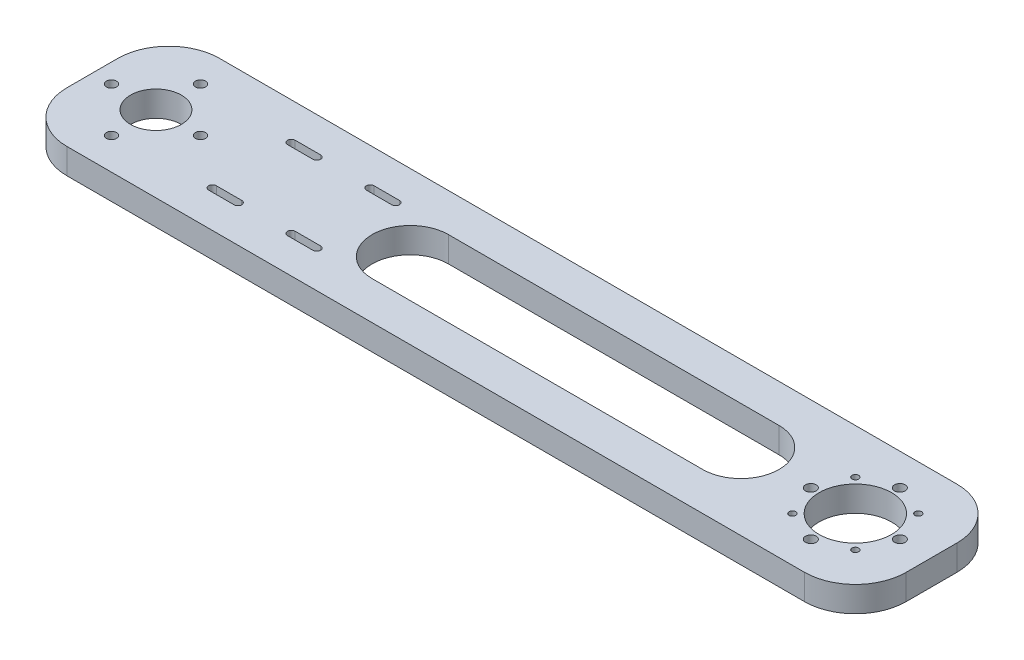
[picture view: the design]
ISO-10303-21;
HEADER;
FILE_DESCRIPTION(('STEP AP214'),'2;1');
FILE_NAME('part.step','',(''),(''),'','','');
FILE_SCHEMA(('AUTOMOTIVE_DESIGN { 1 0 10303 214 1 1 1 1 }'));
ENDSEC;
DATA;
#1=APPLICATION_CONTEXT('core data for automotive mechanical design processes');
#2=APPLICATION_PROTOCOL_DEFINITION('international standard','automotive_design',2000,#1);
#3=PRODUCT_CONTEXT('',#1,'mechanical');
#4=PRODUCT('Part','Part','',(#3));
#5=PRODUCT_RELATED_PRODUCT_CATEGORY('part','',(#4));
#6=PRODUCT_DEFINITION_FORMATION('','',#4);
#7=PRODUCT_DEFINITION_CONTEXT('part definition',#1,'design');
#8=PRODUCT_DEFINITION('design','',#6,#7);
#9=PRODUCT_DEFINITION_SHAPE('','',#8);
#10=(LENGTH_UNIT() NAMED_UNIT(*) SI_UNIT(.MILLI.,.METRE.));
#11=(NAMED_UNIT(*) PLANE_ANGLE_UNIT() SI_UNIT($,.RADIAN.));
#12=(NAMED_UNIT(*) SI_UNIT($,.STERADIAN.) SOLID_ANGLE_UNIT());
#13=UNCERTAINTY_MEASURE_WITH_UNIT(LENGTH_MEASURE(1.E-05),#10,'distance_accuracy_value','');
#14=(GEOMETRIC_REPRESENTATION_CONTEXT(3) GLOBAL_UNCERTAINTY_ASSIGNED_CONTEXT((#13)) GLOBAL_UNIT_ASSIGNED_CONTEXT((#10,
#11,#12)) REPRESENTATION_CONTEXT('',''));
#15=CARTESIAN_POINT('',(0.,0.,0.));
#16=DIRECTION('',(0.,0.,1.));
#17=DIRECTION('',(1.,0.,0.));
#18=AXIS2_PLACEMENT_3D('',#15,#16,#17);
#19=CARTESIAN_POINT('',(165.,10.,30.));
#20=DIRECTION('',(-1.,0.,0.));
#21=DIRECTION('',(0.,0.,1.));
#22=AXIS2_PLACEMENT_3D('',#19,#20,#21);
#23=PLANE('',#22);
#24=DIRECTION('',(0.,0.,-1.));
#25=VECTOR('',#24,1.);
#26=CARTESIAN_POINT('',(165.,0.,30.));
#27=LINE('',#26,#25);
#28=CARTESIAN_POINT('',(165.,0.,10.));
#29=VERTEX_POINT('',#28);
#30=CARTESIAN_POINT('',(165.,0.,-9.99999999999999));
#31=VERTEX_POINT('',#30);
#32=EDGE_CURVE('E468',#29,#31,#27,.T.);
#33=ORIENTED_EDGE('',*,*,#32,.T.);
#34=DIRECTION('',(0.,-1.,0.));
#35=VECTOR('',#34,1.);
#36=CARTESIAN_POINT('',(165.,10.,-9.99999999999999));
#37=LINE('',#36,#35);
#38=CARTESIAN_POINT('',(165.,10.,-9.99999999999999));
#39=VERTEX_POINT('',#38);
#40=EDGE_CURVE('E12',#31,#39,#37,.F.);
#41=ORIENTED_EDGE('',*,*,#40,.T.);
#42=DIRECTION('',(0.,0.,-1.));
#43=VECTOR('',#42,1.);
#44=CARTESIAN_POINT('',(165.,10.,30.));
#45=LINE('',#44,#43);
#46=CARTESIAN_POINT('',(165.,10.,10.));
#47=VERTEX_POINT('',#46);
#48=EDGE_CURVE('E471',#47,#39,#45,.T.);
#49=ORIENTED_EDGE('',*,*,#48,.F.);
#50=DIRECTION('',(0.,-1.,0.));
#51=VECTOR('',#50,1.);
#52=CARTESIAN_POINT('',(165.,10.,10.));
#53=LINE('',#52,#51);
#54=EDGE_CURVE('E58',#47,#29,#53,.T.);
#55=ORIENTED_EDGE('',*,*,#54,.T.);
#56=EDGE_LOOP('',(#33,#41,#49,#55));
#57=FACE_BOUND('',#56,.T.);
#58=ADVANCED_FACE('F55',(#57),#23,.F.);
#59=CARTESIAN_POINT('',(-165.,10.,-30.));
#60=DIRECTION('',(0.,0.,1.));
#61=DIRECTION('',(1.,0.,0.));
#62=AXIS2_PLACEMENT_3D('',#59,#60,#61);
#63=PLANE('',#62);
#64=DIRECTION('',(-1.,0.,0.));
#65=VECTOR('',#64,1.);
#66=CARTESIAN_POINT('',(-165.,0.,-30.));
#67=LINE('',#66,#65);
#68=CARTESIAN_POINT('',(145.,0.,-30.));
#69=VERTEX_POINT('',#68);
#70=CARTESIAN_POINT('',(-145.,0.,-30.));
#71=VERTEX_POINT('',#70);
#72=EDGE_CURVE('E490',#69,#71,#67,.T.);
#73=ORIENTED_EDGE('',*,*,#72,.T.);
#74=DIRECTION('',(0.,-1.,0.));
#75=VECTOR('',#74,1.);
#76=CARTESIAN_POINT('',(-145.,10.,-30.));
#77=LINE('',#76,#75);
#78=CARTESIAN_POINT('',(-145.,10.,-30.));
#79=VERTEX_POINT('',#78);
#80=EDGE_CURVE('E508',#71,#79,#77,.F.);
#81=ORIENTED_EDGE('',*,*,#80,.T.);
#82=DIRECTION('',(-1.,0.,0.));
#83=VECTOR('',#82,1.);
#84=CARTESIAN_POINT('',(-165.,10.,-30.));
#85=LINE('',#84,#83);
#86=CARTESIAN_POINT('',(145.,10.,-30.));
#87=VERTEX_POINT('',#86);
#88=EDGE_CURVE('E473',#87,#79,#85,.T.);
#89=ORIENTED_EDGE('',*,*,#88,.F.);
#90=DIRECTION('',(0.,-1.,0.));
#91=VECTOR('',#90,1.);
#92=CARTESIAN_POINT('',(145.,10.,-30.));
#93=LINE('',#92,#91);
#94=EDGE_CURVE('E510',#87,#69,#93,.T.);
#95=ORIENTED_EDGE('',*,*,#94,.T.);
#96=EDGE_LOOP('',(#73,#81,#89,#95));
#97=FACE_BOUND('',#96,.T.);
#98=ADVANCED_FACE('F545',(#97),#63,.F.);
#99=CARTESIAN_POINT('',(-165.,10.,30.));
#100=DIRECTION('',(1.,0.,0.));
#101=DIRECTION('',(0.,0.,-1.));
#102=AXIS2_PLACEMENT_3D('',#99,#100,#101);
#103=PLANE('',#102);
#104=DIRECTION('',(0.,0.,1.));
#105=VECTOR('',#104,1.);
#106=CARTESIAN_POINT('',(-165.,10.,30.));
#107=LINE('',#106,#105);
#108=CARTESIAN_POINT('',(-165.,10.,-9.99999999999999));
#109=VERTEX_POINT('',#108);
#110=CARTESIAN_POINT('',(-165.,10.,10.));
#111=VERTEX_POINT('',#110);
#112=EDGE_CURVE('E480',#109,#111,#107,.T.);
#113=ORIENTED_EDGE('',*,*,#112,.F.);
#114=DIRECTION('',(0.,-1.,0.));
#115=VECTOR('',#114,1.);
#116=CARTESIAN_POINT('',(-165.,10.,-9.99999999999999));
#117=LINE('',#116,#115);
#118=CARTESIAN_POINT('',(-165.,0.,-9.99999999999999));
#119=VERTEX_POINT('',#118);
#120=EDGE_CURVE('E496',#109,#119,#117,.T.);
#121=ORIENTED_EDGE('',*,*,#120,.T.);
#122=DIRECTION('',(0.,0.,1.));
#123=VECTOR('',#122,1.);
#124=CARTESIAN_POINT('',(-165.,0.,30.));
#125=LINE('',#124,#123);
#126=CARTESIAN_POINT('',(-165.,0.,10.));
#127=VERTEX_POINT('',#126);
#128=EDGE_CURVE('E487',#119,#127,#125,.T.);
#129=ORIENTED_EDGE('',*,*,#128,.T.);
#130=DIRECTION('',(0.,-1.,0.));
#131=VECTOR('',#130,1.);
#132=CARTESIAN_POINT('',(-165.,10.,10.));
#133=LINE('',#132,#131);
#134=EDGE_CURVE('E485',#127,#111,#133,.F.);
#135=ORIENTED_EDGE('',*,*,#134,.T.);
#136=EDGE_LOOP('',(#113,#121,#129,#135));
#137=FACE_BOUND('',#136,.T.);
#138=ADVANCED_FACE('F551',(#137),#103,.F.);
#139=CARTESIAN_POINT('',(-165.,10.,30.));
#140=DIRECTION('',(0.,0.,-1.));
#141=DIRECTION('',(-1.,0.,0.));
#142=AXIS2_PLACEMENT_3D('',#139,#140,#141);
#143=PLANE('',#142);
#144=DIRECTION('',(1.,0.,0.));
#145=VECTOR('',#144,1.);
#146=CARTESIAN_POINT('',(-165.,10.,30.));
#147=LINE('',#146,#145);
#148=CARTESIAN_POINT('',(-145.,10.,30.));
#149=VERTEX_POINT('',#148);
#150=CARTESIAN_POINT('',(145.,10.,30.));
#151=VERTEX_POINT('',#150);
#152=EDGE_CURVE('E483',#149,#151,#147,.T.);
#153=ORIENTED_EDGE('',*,*,#152,.F.);
#154=DIRECTION('',(0.,-1.,0.));
#155=VECTOR('',#154,1.);
#156=CARTESIAN_POINT('',(-145.,10.,30.));
#157=LINE('',#156,#155);
#158=CARTESIAN_POINT('',(-145.,0.,30.));
#159=VERTEX_POINT('',#158);
#160=EDGE_CURVE('E522',#149,#159,#157,.T.);
#161=ORIENTED_EDGE('',*,*,#160,.T.);
#162=DIRECTION('',(1.,0.,0.));
#163=VECTOR('',#162,1.);
#164=CARTESIAN_POINT('',(-165.,0.,30.));
#165=LINE('',#164,#163);
#166=CARTESIAN_POINT('',(145.,0.,30.));
#167=VERTEX_POINT('',#166);
#168=EDGE_CURVE('E475',#159,#167,#165,.T.);
#169=ORIENTED_EDGE('',*,*,#168,.T.);
#170=DIRECTION('',(0.,-1.,0.));
#171=VECTOR('',#170,1.);
#172=CARTESIAN_POINT('',(145.,10.,30.));
#173=LINE('',#172,#171);
#174=EDGE_CURVE('E519',#167,#151,#173,.F.);
#175=ORIENTED_EDGE('',*,*,#174,.T.);
#176=EDGE_LOOP('',(#153,#161,#169,#175));
#177=FACE_BOUND('',#176,.T.);
#178=ADVANCED_FACE('F559',(#177),#143,.F.);
#179=CARTESIAN_POINT('',(0.,10.,0.));
#180=DIRECTION('',(0.,-1.,0.));
#181=DIRECTION('',(0.,0.,-1.));
#182=AXIS2_PLACEMENT_3D('',#179,#180,#181);
#183=PLANE('',#182);
#184=CARTESIAN_POINT('',(-122.499999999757,10.,1.13742348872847E-10));
#185=DIRECTION('',(0.,1.,0.));
#186=DIRECTION('',(-1.,0.,0.));
#187=AXIS2_PLACEMENT_3D('',#184,#185,#186);
#188=CIRCLE('',#187,2.);
#189=CARTESIAN_POINT('',(-124.499999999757,10.,1.1373536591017E-10));
#190=VERTEX_POINT('',#189);
#191=EDGE_CURVE('E1002',#190,#190,#188,.T.);
#192=ORIENTED_EDGE('',*,*,#191,.F.);
#193=EDGE_LOOP('',(#192));
#194=FACE_BOUND('',#193,.T.);
#195=CARTESIAN_POINT('',(-140.,10.,17.5000000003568));
#196=DIRECTION('',(0.,1.,0.));
#197=DIRECTION('',(0.,0.,-1.));
#198=AXIS2_PLACEMENT_3D('',#195,#196,#197);
#199=CIRCLE('',#198,2.);
#200=CARTESIAN_POINT('',(-140.,10.,15.5000000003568));
#201=VERTEX_POINT('',#200);
#202=EDGE_CURVE('E998',#201,#201,#199,.T.);
#203=ORIENTED_EDGE('',*,*,#202,.F.);
#204=EDGE_LOOP('',(#203));
#205=FACE_BOUND('',#204,.T.);
#206=CARTESIAN_POINT('',(-157.500000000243,10.,1.13492548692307E-10));
#207=DIRECTION('',(0.,1.,0.));
#208=DIRECTION('',(1.,0.,0.));
#209=AXIS2_PLACEMENT_3D('',#206,#207,#208);
#210=CIRCLE('',#209,2.);
#211=CARTESIAN_POINT('',(-155.500000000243,10.,1.1351349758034E-10));
#212=VERTEX_POINT('',#211);
#213=EDGE_CURVE('E259',#212,#212,#210,.T.);
#214=ORIENTED_EDGE('',*,*,#213,.F.);
#215=EDGE_LOOP('',(#214));
#216=FACE_BOUND('',#215,.T.);
#217=DIRECTION('',(1.,0.,0.));
#218=VECTOR('',#217,1.);
#219=CARTESIAN_POINT('',(-40.,10.,15.));
#220=LINE('',#219,#218);
#221=CARTESIAN_POINT('',(-40.,10.,15.));
#222=VERTEX_POINT('',#221);
#223=CARTESIAN_POINT('',(90.,10.,15.));
#224=VERTEX_POINT('',#223);
#225=EDGE_CURVE('E266',#222,#224,#220,.T.);
#226=ORIENTED_EDGE('',*,*,#225,.F.);
#227=CARTESIAN_POINT('',(-40.,10.,0.));
#228=DIRECTION('',(0.,1.,0.));
#229=DIRECTION('',(0.,0.,1.));
#230=AXIS2_PLACEMENT_3D('',#227,#228,#229);
#231=CIRCLE('',#230,15.);
#232=CARTESIAN_POINT('',(-40.,10.,-15.));
#233=VERTEX_POINT('',#232);
#234=EDGE_CURVE('E70',#233,#222,#231,.T.);
#235=ORIENTED_EDGE('',*,*,#234,.F.);
#236=DIRECTION('',(-1.,0.,0.));
#237=VECTOR('',#236,1.);
#238=CARTESIAN_POINT('',(-40.,10.,-15.));
#239=LINE('',#238,#237);
#240=CARTESIAN_POINT('',(90.,10.,-15.));
#241=VERTEX_POINT('',#240);
#242=EDGE_CURVE('E253',#241,#233,#239,.T.);
#243=ORIENTED_EDGE('',*,*,#242,.F.);
#244=CARTESIAN_POINT('',(90.,10.,0.));
#245=DIRECTION('',(0.,1.,0.));
#246=DIRECTION('',(0.,0.,1.));
#247=AXIS2_PLACEMENT_3D('',#244,#245,#246);
#248=CIRCLE('',#247,15.);
#249=EDGE_CURVE('E257',#224,#241,#248,.T.);
#250=ORIENTED_EDGE('',*,*,#249,.F.);
#251=EDGE_LOOP('',(#226,#235,#243,#250));
#252=FACE_BOUND('',#251,.T.);
#253=CARTESIAN_POINT('',(135.,10.,17.5));
#254=DIRECTION('',(0.,-1.,0.));
#255=DIRECTION('',(0.,0.,-1.));
#256=AXIS2_PLACEMENT_3D('',#253,#254,#255);
#257=CIRCLE('',#256,2.09999999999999);
#258=CARTESIAN_POINT('',(135.,10.,15.4));
#259=VERTEX_POINT('',#258);
#260=EDGE_CURVE('E280',#259,#259,#257,.T.);
#261=ORIENTED_EDGE('',*,*,#260,.T.);
#262=EDGE_LOOP('',(#261));
#263=FACE_BOUND('',#262,.T.);
#264=CARTESIAN_POINT('',(152.5,10.,0.));
#265=DIRECTION('',(0.,-1.,0.));
#266=DIRECTION('',(0.,0.,-1.));
#267=AXIS2_PLACEMENT_3D('',#264,#265,#266);
#268=CIRCLE('',#267,2.09999999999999);
#269=CARTESIAN_POINT('',(152.5,10.,-2.09999999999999));
#270=VERTEX_POINT('',#269);
#271=EDGE_CURVE('E286',#270,#270,#268,.T.);
#272=ORIENTED_EDGE('',*,*,#271,.T.);
#273=EDGE_LOOP('',(#272));
#274=FACE_BOUND('',#273,.T.);
#275=CARTESIAN_POINT('',(117.5,10.,0.));
#276=DIRECTION('',(0.,-1.,0.));
#277=DIRECTION('',(0.,0.,-1.));
#278=AXIS2_PLACEMENT_3D('',#275,#276,#277);
#279=CIRCLE('',#278,2.1);
#280=CARTESIAN_POINT('',(117.5,10.,-2.1));
#281=VERTEX_POINT('',#280);
#282=EDGE_CURVE('E293',#281,#281,#279,.T.);
#283=ORIENTED_EDGE('',*,*,#282,.T.);
#284=EDGE_LOOP('',(#283));
#285=FACE_BOUND('',#284,.T.);
#286=CARTESIAN_POINT('',(135.,10.,-17.5));
#287=DIRECTION('',(0.,-1.,0.));
#288=DIRECTION('',(0.,0.,-1.));
#289=AXIS2_PLACEMENT_3D('',#286,#287,#288);
#290=CIRCLE('',#289,2.09999999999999);
#291=CARTESIAN_POINT('',(135.,10.,-19.6));
#292=VERTEX_POINT('',#291);
#293=EDGE_CURVE('E273',#292,#292,#290,.T.);
#294=ORIENTED_EDGE('',*,*,#293,.T.);
#295=EDGE_LOOP('',(#294));
#296=FACE_BOUND('',#295,.T.);
#297=CARTESIAN_POINT('',(-140.,10.,-17.5000000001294));
#298=DIRECTION('',(0.,1.,0.));
#299=DIRECTION('',(0.,0.,1.));
#300=AXIS2_PLACEMENT_3D('',#297,#298,#299);
#301=CIRCLE('',#300,2.);
#302=CARTESIAN_POINT('',(-140.,10.,-15.5000000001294));
#303=VERTEX_POINT('',#302);
#304=EDGE_CURVE('E279',#303,#303,#301,.T.);
#305=ORIENTED_EDGE('',*,*,#304,.F.);
#306=EDGE_LOOP('',(#305));
#307=FACE_BOUND('',#306,.T.);
#308=DIRECTION('',(-1.,0.,0.));
#309=VECTOR('',#308,1.);
#310=CARTESIAN_POINT('',(-102.265379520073,10.,-14.));
#311=LINE('',#310,#309);
#312=CARTESIAN_POINT('',(-92.2653795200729,10.,-14.));
#313=VERTEX_POINT('',#312);
#314=CARTESIAN_POINT('',(-102.265379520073,10.,-14.));
#315=VERTEX_POINT('',#314);
#316=EDGE_CURVE('E345',#313,#315,#311,.T.);
#317=ORIENTED_EDGE('',*,*,#316,.T.);
#318=CARTESIAN_POINT('',(-102.265379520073,10.,-15.5));
#319=DIRECTION('',(0.,-1.,0.));
#320=DIRECTION('',(0.,0.,1.));
#321=AXIS2_PLACEMENT_3D('',#318,#319,#320);
#322=CIRCLE('',#321,1.50000000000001);
#323=CARTESIAN_POINT('',(-102.265379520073,10.,-17.));
#324=VERTEX_POINT('',#323);
#325=EDGE_CURVE('E353',#315,#324,#322,.T.);
#326=ORIENTED_EDGE('',*,*,#325,.T.);
#327=DIRECTION('',(1.,0.,0.));
#328=VECTOR('',#327,1.);
#329=CARTESIAN_POINT('',(-102.265379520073,10.,-17.));
#330=LINE('',#329,#328);
#331=CARTESIAN_POINT('',(-92.2653795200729,10.,-17.));
#332=VERTEX_POINT('',#331);
#333=EDGE_CURVE('E368',#324,#332,#330,.T.);
#334=ORIENTED_EDGE('',*,*,#333,.T.);
#335=CARTESIAN_POINT('',(-92.2653795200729,10.,-15.5));
#336=DIRECTION('',(0.,-1.,0.));
#337=DIRECTION('',(0.,0.,1.));
#338=AXIS2_PLACEMENT_3D('',#335,#336,#337);
#339=CIRCLE('',#338,1.49999999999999);
#340=EDGE_CURVE('E362',#332,#313,#339,.T.);
#341=ORIENTED_EDGE('',*,*,#340,.T.);
#342=EDGE_LOOP('',(#317,#326,#334,#341));
#343=FACE_BOUND('',#342,.T.);
#344=DIRECTION('',(-1.,0.,0.));
#345=VECTOR('',#344,1.);
#346=CARTESIAN_POINT('',(-71.2653795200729,10.,17.));
#347=LINE('',#346,#345);
#348=CARTESIAN_POINT('',(-61.2653795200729,10.,17.));
#349=VERTEX_POINT('',#348);
#350=CARTESIAN_POINT('',(-71.2653795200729,10.,17.));
#351=VERTEX_POINT('',#350);
#352=EDGE_CURVE('E379',#349,#351,#347,.T.);
#353=ORIENTED_EDGE('',*,*,#352,.T.);
#354=CARTESIAN_POINT('',(-71.2653795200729,10.,15.5));
#355=DIRECTION('',(0.,-1.,0.));
#356=DIRECTION('',(0.,0.,-1.));
#357=AXIS2_PLACEMENT_3D('',#354,#355,#356);
#358=CIRCLE('',#357,1.5);
#359=CARTESIAN_POINT('',(-71.2653795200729,10.,14.));
#360=VERTEX_POINT('',#359);
#361=EDGE_CURVE('E389',#351,#360,#358,.T.);
#362=ORIENTED_EDGE('',*,*,#361,.T.);
#363=DIRECTION('',(1.,0.,0.));
#364=VECTOR('',#363,1.);
#365=CARTESIAN_POINT('',(-71.2653795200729,10.,14.));
#366=LINE('',#365,#364);
#367=CARTESIAN_POINT('',(-61.2653795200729,10.,14.));
#368=VERTEX_POINT('',#367);
#369=EDGE_CURVE('E399',#360,#368,#366,.T.);
#370=ORIENTED_EDGE('',*,*,#369,.T.);
#371=CARTESIAN_POINT('',(-61.2653795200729,10.,15.5));
#372=DIRECTION('',(0.,-1.,0.));
#373=DIRECTION('',(0.,0.,-1.));
#374=AXIS2_PLACEMENT_3D('',#371,#372,#373);
#375=CIRCLE('',#374,1.5);
#376=EDGE_CURVE('E394',#368,#349,#375,.T.);
#377=ORIENTED_EDGE('',*,*,#376,.T.);
#378=EDGE_LOOP('',(#353,#362,#370,#377));
#379=FACE_BOUND('',#378,.T.);
#380=DIRECTION('',(-1.,0.,0.));
#381=VECTOR('',#380,1.);
#382=CARTESIAN_POINT('',(-71.2653795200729,10.,-14.));
#383=LINE('',#382,#381);
#384=CARTESIAN_POINT('',(-61.2653795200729,10.,-14.));
#385=VERTEX_POINT('',#384);
#386=CARTESIAN_POINT('',(-71.2653795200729,10.,-14.));
#387=VERTEX_POINT('',#386);
#388=EDGE_CURVE('E308',#385,#387,#383,.T.);
#389=ORIENTED_EDGE('',*,*,#388,.T.);
#390=CARTESIAN_POINT('',(-71.2653795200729,10.,-15.5));
#391=DIRECTION('',(0.,-1.,0.));
#392=DIRECTION('',(0.,0.,1.));
#393=AXIS2_PLACEMENT_3D('',#390,#391,#392);
#394=CIRCLE('',#393,1.5);
#395=CARTESIAN_POINT('',(-71.2653795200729,10.,-17.));
#396=VERTEX_POINT('',#395);
#397=EDGE_CURVE('E319',#387,#396,#394,.T.);
#398=ORIENTED_EDGE('',*,*,#397,.T.);
#399=DIRECTION('',(1.,0.,0.));
#400=VECTOR('',#399,1.);
#401=CARTESIAN_POINT('',(-71.2653795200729,10.,-17.));
#402=LINE('',#401,#400);
#403=CARTESIAN_POINT('',(-61.2653795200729,10.,-17.));
#404=VERTEX_POINT('',#403);
#405=EDGE_CURVE('E335',#396,#404,#402,.T.);
#406=ORIENTED_EDGE('',*,*,#405,.T.);
#407=CARTESIAN_POINT('',(-61.2653795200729,10.,-15.5));
#408=DIRECTION('',(0.,-1.,0.));
#409=DIRECTION('',(0.,0.,1.));
#410=AXIS2_PLACEMENT_3D('',#407,#408,#409);
#411=CIRCLE('',#410,1.5);
#412=EDGE_CURVE('E333',#404,#385,#411,.T.);
#413=ORIENTED_EDGE('',*,*,#412,.T.);
#414=EDGE_LOOP('',(#389,#398,#406,#413));
#415=FACE_BOUND('',#414,.T.);
#416=DIRECTION('',(-1.,0.,0.));
#417=VECTOR('',#416,1.);
#418=CARTESIAN_POINT('',(-102.265379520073,10.,17.));
#419=LINE('',#418,#417);
#420=CARTESIAN_POINT('',(-92.2653795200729,10.,17.));
#421=VERTEX_POINT('',#420);
#422=CARTESIAN_POINT('',(-102.265379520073,10.,17.));
#423=VERTEX_POINT('',#422);
#424=EDGE_CURVE('E411',#421,#423,#419,.T.);
#425=ORIENTED_EDGE('',*,*,#424,.T.);
#426=CARTESIAN_POINT('',(-102.265379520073,10.,15.5));
#427=DIRECTION('',(0.,-1.,0.));
#428=DIRECTION('',(0.,0.,-1.));
#429=AXIS2_PLACEMENT_3D('',#426,#427,#428);
#430=CIRCLE('',#429,1.50000000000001);
#431=CARTESIAN_POINT('',(-102.265379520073,10.,14.));
#432=VERTEX_POINT('',#431);
#433=EDGE_CURVE('E405',#423,#432,#430,.T.);
#434=ORIENTED_EDGE('',*,*,#433,.T.);
#435=DIRECTION('',(1.,0.,0.));
#436=VECTOR('',#435,1.);
#437=CARTESIAN_POINT('',(-102.265379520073,10.,14.));
#438=LINE('',#437,#436);
#439=CARTESIAN_POINT('',(-92.2653795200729,10.,14.));
#440=VERTEX_POINT('',#439);
#441=EDGE_CURVE('E408',#432,#440,#438,.T.);
#442=ORIENTED_EDGE('',*,*,#441,.T.);
#443=CARTESIAN_POINT('',(-92.2653795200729,10.,15.5));
#444=DIRECTION('',(0.,-1.,0.));
#445=DIRECTION('',(0.,0.,-1.));
#446=AXIS2_PLACEMENT_3D('',#443,#444,#445);
#447=CIRCLE('',#446,1.49999999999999);
#448=EDGE_CURVE('E409',#440,#421,#447,.T.);
#449=ORIENTED_EDGE('',*,*,#448,.T.);
#450=EDGE_LOOP('',(#425,#434,#442,#449));
#451=FACE_BOUND('',#450,.T.);
#452=CARTESIAN_POINT('',(122.625631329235,10.,-12.3743686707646));
#453=DIRECTION('',(0.,-1.,0.));
#454=DIRECTION('',(0.,0.,-1.));
#455=AXIS2_PLACEMENT_3D('',#452,#453,#454);
#456=CIRCLE('',#455,1.29999999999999);
#457=CARTESIAN_POINT('',(122.625631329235,10.,-13.6743686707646));
#458=VERTEX_POINT('',#457);
#459=EDGE_CURVE('E427',#458,#458,#456,.T.);
#460=ORIENTED_EDGE('',*,*,#459,.T.);
#461=EDGE_LOOP('',(#460));
#462=FACE_BOUND('',#461,.T.);
#463=CARTESIAN_POINT('',(147.374368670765,10.,-12.3743686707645));
#464=DIRECTION('',(0.,-1.,0.));
#465=DIRECTION('',(0.,0.,-1.));
#466=AXIS2_PLACEMENT_3D('',#463,#464,#465);
#467=CIRCLE('',#466,1.30000000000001);
#468=CARTESIAN_POINT('',(147.374368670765,10.,-13.6743686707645));
#469=VERTEX_POINT('',#468);
#470=EDGE_CURVE('E444',#469,#469,#467,.T.);
#471=ORIENTED_EDGE('',*,*,#470,.T.);
#472=EDGE_LOOP('',(#471));
#473=FACE_BOUND('',#472,.T.);
#474=CARTESIAN_POINT('',(147.374368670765,10.,12.3743686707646));
#475=DIRECTION('',(0.,-1.,0.));
#476=DIRECTION('',(0.,0.,-1.));
#477=AXIS2_PLACEMENT_3D('',#474,#475,#476);
#478=CIRCLE('',#477,1.30000000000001);
#479=CARTESIAN_POINT('',(147.374368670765,10.,11.0743686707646));
#480=VERTEX_POINT('',#479);
#481=EDGE_CURVE('E438',#480,#480,#478,.T.);
#482=ORIENTED_EDGE('',*,*,#481,.T.);
#483=EDGE_LOOP('',(#482));
#484=FACE_BOUND('',#483,.T.);
#485=CARTESIAN_POINT('',(122.625631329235,10.,12.3743686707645));
#486=DIRECTION('',(0.,-1.,0.));
#487=DIRECTION('',(0.,0.,-1.));
#488=AXIS2_PLACEMENT_3D('',#485,#486,#487);
#489=CIRCLE('',#488,1.29999999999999);
#490=CARTESIAN_POINT('',(122.625631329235,10.,11.0743686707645));
#491=VERTEX_POINT('',#490);
#492=EDGE_CURVE('E455',#491,#491,#489,.T.);
#493=ORIENTED_EDGE('',*,*,#492,.T.);
#494=EDGE_LOOP('',(#493));
#495=FACE_BOUND('',#494,.T.);
#496=CARTESIAN_POINT('',(135.,10.,0.));
#497=DIRECTION('',(0.,-1.,0.));
#498=DIRECTION('',(0.,0.,-1.));
#499=AXIS2_PLACEMENT_3D('',#496,#497,#498);
#500=CIRCLE('',#499,14.25);
#501=CARTESIAN_POINT('',(135.,10.,-14.25));
#502=VERTEX_POINT('',#501);
#503=EDGE_CURVE('E459',#502,#502,#500,.T.);
#504=ORIENTED_EDGE('',*,*,#503,.T.);
#505=EDGE_LOOP('',(#504));
#506=FACE_BOUND('',#505,.T.);
#507=CARTESIAN_POINT('',(-140.,10.,1.13697246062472E-10));
#508=DIRECTION('',(0.,-1.,0.));
#509=DIRECTION('',(0.,0.,-1.));
#510=AXIS2_PLACEMENT_3D('',#507,#508,#509);
#511=CIRCLE('',#510,9.99999999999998);
#512=CARTESIAN_POINT('',(-140.,10.,-9.99999999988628));
#513=VERTEX_POINT('',#512);
#514=EDGE_CURVE('E462',#513,#513,#511,.T.);
#515=ORIENTED_EDGE('',*,*,#514,.T.);
#516=EDGE_LOOP('',(#515));
#517=FACE_BOUND('',#516,.T.);
#518=ORIENTED_EDGE('',*,*,#88,.T.);
#519=CARTESIAN_POINT('',(-145.,10.,-9.99999999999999));
#520=DIRECTION('',(0.,-1.,0.));
#521=DIRECTION('',(0.,0.,-1.));
#522=AXIS2_PLACEMENT_3D('',#519,#520,#521);
#523=CIRCLE('',#522,20.);
#524=EDGE_CURVE('E518',#79,#109,#523,.F.);
#525=ORIENTED_EDGE('',*,*,#524,.T.);
#526=ORIENTED_EDGE('',*,*,#112,.T.);
#527=CARTESIAN_POINT('',(-145.,10.,10.));
#528=DIRECTION('',(0.,-1.,0.));
#529=DIRECTION('',(0.,0.,-1.));
#530=AXIS2_PLACEMENT_3D('',#527,#528,#529);
#531=CIRCLE('',#530,20.);
#532=EDGE_CURVE('E516',#111,#149,#531,.F.);
#533=ORIENTED_EDGE('',*,*,#532,.T.);
#534=ORIENTED_EDGE('',*,*,#152,.T.);
#535=CARTESIAN_POINT('',(145.,10.,10.));
#536=DIRECTION('',(0.,-1.,0.));
#537=DIRECTION('',(0.,0.,-1.));
#538=AXIS2_PLACEMENT_3D('',#535,#536,#537);
#539=CIRCLE('',#538,20.);
#540=EDGE_CURVE('E511',#151,#47,#539,.F.);
#541=ORIENTED_EDGE('',*,*,#540,.T.);
#542=ORIENTED_EDGE('',*,*,#48,.T.);
#543=CARTESIAN_POINT('',(145.,10.,-10.));
#544=DIRECTION('',(0.,-1.,0.));
#545=DIRECTION('',(0.,0.,-1.));
#546=AXIS2_PLACEMENT_3D('',#543,#544,#545);
#547=CIRCLE('',#546,20.);
#548=EDGE_CURVE('E513',#39,#87,#547,.F.);
#549=ORIENTED_EDGE('',*,*,#548,.T.);
#550=EDGE_LOOP('',(#518,#525,#526,#533,#534,#541,#542,#549));
#551=FACE_BOUND('',#550,.T.);
#552=ADVANCED_FACE('F546',(#194,#205,#216,#252,#263,#274,#285,#296,#307,#343,#379,#415,#451,
#462,#473,#484,#495,#506,#517,#551),#183,.F.);
#553=CARTESIAN_POINT('',(0.,0.,0.));
#554=DIRECTION('',(0.,-1.,0.));
#555=DIRECTION('',(0.,0.,-1.));
#556=AXIS2_PLACEMENT_3D('',#553,#554,#555);
#557=PLANE('',#556);
#558=CARTESIAN_POINT('',(-122.499999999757,0.,1.13742348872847E-10));
#559=DIRECTION('',(0.,1.,0.));
#560=DIRECTION('',(-1.,0.,0.));
#561=AXIS2_PLACEMENT_3D('',#558,#559,#560);
#562=CIRCLE('',#561,2.);
#563=CARTESIAN_POINT('',(-124.499999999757,0.,1.1373536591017E-10));
#564=VERTEX_POINT('',#563);
#565=EDGE_CURVE('E270',#564,#564,#562,.T.);
#566=ORIENTED_EDGE('',*,*,#565,.T.);
#567=EDGE_LOOP('',(#566));
#568=FACE_BOUND('',#567,.T.);
#569=CARTESIAN_POINT('',(-140.,0.,17.5000000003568));
#570=DIRECTION('',(0.,1.,0.));
#571=DIRECTION('',(0.,0.,-1.));
#572=AXIS2_PLACEMENT_3D('',#569,#570,#571);
#573=CIRCLE('',#572,2.);
#574=CARTESIAN_POINT('',(-140.,0.,15.5000000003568));
#575=VERTEX_POINT('',#574);
#576=EDGE_CURVE('E994',#575,#575,#573,.T.);
#577=ORIENTED_EDGE('',*,*,#576,.T.);
#578=EDGE_LOOP('',(#577));
#579=FACE_BOUND('',#578,.T.);
#580=CARTESIAN_POINT('',(-157.500000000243,0.,1.13492548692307E-10));
#581=DIRECTION('',(0.,1.,0.));
#582=DIRECTION('',(1.,0.,0.));
#583=AXIS2_PLACEMENT_3D('',#580,#581,#582);
#584=CIRCLE('',#583,2.);
#585=CARTESIAN_POINT('',(-155.500000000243,0.,1.1351349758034E-10));
#586=VERTEX_POINT('',#585);
#587=EDGE_CURVE('E999',#586,#586,#584,.T.);
#588=ORIENTED_EDGE('',*,*,#587,.T.);
#589=EDGE_LOOP('',(#588));
#590=FACE_BOUND('',#589,.T.);
#591=CARTESIAN_POINT('',(-40.,0.,0.));
#592=DIRECTION('',(0.,1.,0.));
#593=DIRECTION('',(0.,0.,1.));
#594=AXIS2_PLACEMENT_3D('',#591,#592,#593);
#595=CIRCLE('',#594,15.);
#596=CARTESIAN_POINT('',(-40.,0.,-15.));
#597=VERTEX_POINT('',#596);
#598=CARTESIAN_POINT('',(-40.,0.,15.));
#599=VERTEX_POINT('',#598);
#600=EDGE_CURVE('E240',#597,#599,#595,.T.);
#601=ORIENTED_EDGE('',*,*,#600,.T.);
#602=DIRECTION('',(1.,0.,0.));
#603=VECTOR('',#602,1.);
#604=CARTESIAN_POINT('',(-40.,0.,15.));
#605=LINE('',#604,#603);
#606=CARTESIAN_POINT('',(90.,0.,15.));
#607=VERTEX_POINT('',#606);
#608=EDGE_CURVE('E247',#599,#607,#605,.T.);
#609=ORIENTED_EDGE('',*,*,#608,.T.);
#610=CARTESIAN_POINT('',(90.,0.,0.));
#611=DIRECTION('',(0.,1.,0.));
#612=DIRECTION('',(0.,0.,1.));
#613=AXIS2_PLACEMENT_3D('',#610,#611,#612);
#614=CIRCLE('',#613,15.);
#615=CARTESIAN_POINT('',(90.,0.,-15.));
#616=VERTEX_POINT('',#615);
#617=EDGE_CURVE('E75',#607,#616,#614,.T.);
#618=ORIENTED_EDGE('',*,*,#617,.T.);
#619=DIRECTION('',(-1.,0.,0.));
#620=VECTOR('',#619,1.);
#621=CARTESIAN_POINT('',(-40.,0.,-15.));
#622=LINE('',#621,#620);
#623=EDGE_CURVE('E242',#616,#597,#622,.T.);
#624=ORIENTED_EDGE('',*,*,#623,.T.);
#625=EDGE_LOOP('',(#601,#609,#618,#624));
#626=FACE_BOUND('',#625,.T.);
#627=CARTESIAN_POINT('',(135.,0.,17.5));
#628=DIRECTION('',(0.,-1.,0.));
#629=DIRECTION('',(0.,0.,-1.));
#630=AXIS2_PLACEMENT_3D('',#627,#628,#629);
#631=CIRCLE('',#630,2.09999999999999);
#632=CARTESIAN_POINT('',(135.,0.,15.4));
#633=VERTEX_POINT('',#632);
#634=EDGE_CURVE('E282',#633,#633,#631,.T.);
#635=ORIENTED_EDGE('',*,*,#634,.F.);
#636=EDGE_LOOP('',(#635));
#637=FACE_BOUND('',#636,.T.);
#638=CARTESIAN_POINT('',(152.5,0.,0.));
#639=DIRECTION('',(0.,-1.,0.));
#640=DIRECTION('',(0.,0.,-1.));
#641=AXIS2_PLACEMENT_3D('',#638,#639,#640);
#642=CIRCLE('',#641,2.09999999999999);
#643=CARTESIAN_POINT('',(152.5,0.,-2.09999999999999));
#644=VERTEX_POINT('',#643);
#645=EDGE_CURVE('E281',#644,#644,#642,.T.);
#646=ORIENTED_EDGE('',*,*,#645,.F.);
#647=EDGE_LOOP('',(#646));
#648=FACE_BOUND('',#647,.T.);
#649=CARTESIAN_POINT('',(117.5,0.,0.));
#650=DIRECTION('',(0.,-1.,0.));
#651=DIRECTION('',(0.,0.,-1.));
#652=AXIS2_PLACEMENT_3D('',#649,#650,#651);
#653=CIRCLE('',#652,2.1);
#654=CARTESIAN_POINT('',(117.5,0.,-2.1));
#655=VERTEX_POINT('',#654);
#656=EDGE_CURVE('E287',#655,#655,#653,.T.);
#657=ORIENTED_EDGE('',*,*,#656,.F.);
#658=EDGE_LOOP('',(#657));
#659=FACE_BOUND('',#658,.T.);
#660=CARTESIAN_POINT('',(135.,0.,-17.5));
#661=DIRECTION('',(0.,-1.,0.));
#662=DIRECTION('',(0.,0.,-1.));
#663=AXIS2_PLACEMENT_3D('',#660,#661,#662);
#664=CIRCLE('',#663,2.09999999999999);
#665=CARTESIAN_POINT('',(135.,0.,-19.6));
#666=VERTEX_POINT('',#665);
#667=EDGE_CURVE('E296',#666,#666,#664,.T.);
#668=ORIENTED_EDGE('',*,*,#667,.F.);
#669=EDGE_LOOP('',(#668));
#670=FACE_BOUND('',#669,.T.);
#671=CARTESIAN_POINT('',(-140.,0.,-17.5000000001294));
#672=DIRECTION('',(0.,1.,0.));
#673=DIRECTION('',(0.,0.,1.));
#674=AXIS2_PLACEMENT_3D('',#671,#672,#673);
#675=CIRCLE('',#674,2.);
#676=CARTESIAN_POINT('',(-140.,0.,-15.5000000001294));
#677=VERTEX_POINT('',#676);
#678=EDGE_CURVE('E304',#677,#677,#675,.T.);
#679=ORIENTED_EDGE('',*,*,#678,.T.);
#680=EDGE_LOOP('',(#679));
#681=FACE_BOUND('',#680,.T.);
#682=CARTESIAN_POINT('',(-102.265379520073,0.,-15.5));
#683=DIRECTION('',(0.,-1.,0.));
#684=DIRECTION('',(0.,0.,1.));
#685=AXIS2_PLACEMENT_3D('',#682,#683,#684);
#686=CIRCLE('',#685,1.50000000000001);
#687=CARTESIAN_POINT('',(-102.265379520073,0.,-14.));
#688=VERTEX_POINT('',#687);
#689=CARTESIAN_POINT('',(-102.265379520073,0.,-17.));
#690=VERTEX_POINT('',#689);
#691=EDGE_CURVE('E358',#688,#690,#686,.T.);
#692=ORIENTED_EDGE('',*,*,#691,.F.);
#693=DIRECTION('',(-1.,0.,0.));
#694=VECTOR('',#693,1.);
#695=CARTESIAN_POINT('',(-102.265379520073,0.,-14.));
#696=LINE('',#695,#694);
#697=CARTESIAN_POINT('',(-92.2653795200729,0.,-14.));
#698=VERTEX_POINT('',#697);
#699=EDGE_CURVE('E349',#698,#688,#696,.T.);
#700=ORIENTED_EDGE('',*,*,#699,.F.);
#701=CARTESIAN_POINT('',(-92.2653795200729,0.,-15.5));
#702=DIRECTION('',(0.,-1.,0.));
#703=DIRECTION('',(0.,0.,1.));
#704=AXIS2_PLACEMENT_3D('',#701,#702,#703);
#705=CIRCLE('',#704,1.49999999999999);
#706=CARTESIAN_POINT('',(-92.2653795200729,0.,-17.));
#707=VERTEX_POINT('',#706);
#708=EDGE_CURVE('E352',#707,#698,#705,.T.);
#709=ORIENTED_EDGE('',*,*,#708,.F.);
#710=DIRECTION('',(1.,0.,0.));
#711=VECTOR('',#710,1.);
#712=CARTESIAN_POINT('',(-102.265379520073,0.,-17.));
#713=LINE('',#712,#711);
#714=EDGE_CURVE('E360',#690,#707,#713,.T.);
#715=ORIENTED_EDGE('',*,*,#714,.F.);
#716=EDGE_LOOP('',(#692,#700,#709,#715));
#717=FACE_BOUND('',#716,.T.);
#718=CARTESIAN_POINT('',(-71.2653795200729,0.,15.5));
#719=DIRECTION('',(0.,-1.,0.));
#720=DIRECTION('',(0.,0.,-1.));
#721=AXIS2_PLACEMENT_3D('',#718,#719,#720);
#722=CIRCLE('',#721,1.5);
#723=CARTESIAN_POINT('',(-71.2653795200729,0.,17.));
#724=VERTEX_POINT('',#723);
#725=CARTESIAN_POINT('',(-71.2653795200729,0.,14.));
#726=VERTEX_POINT('',#725);
#727=EDGE_CURVE('E347',#724,#726,#722,.T.);
#728=ORIENTED_EDGE('',*,*,#727,.F.);
#729=DIRECTION('',(-1.,0.,0.));
#730=VECTOR('',#729,1.);
#731=CARTESIAN_POINT('',(-71.2653795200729,0.,17.));
#732=LINE('',#731,#730);
#733=CARTESIAN_POINT('',(-61.2653795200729,0.,17.));
#734=VERTEX_POINT('',#733);
#735=EDGE_CURVE('E385',#734,#724,#732,.T.);
#736=ORIENTED_EDGE('',*,*,#735,.F.);
#737=CARTESIAN_POINT('',(-61.2653795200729,0.,15.5));
#738=DIRECTION('',(0.,-1.,0.));
#739=DIRECTION('',(0.,0.,-1.));
#740=AXIS2_PLACEMENT_3D('',#737,#738,#739);
#741=CIRCLE('',#740,1.5);
#742=CARTESIAN_POINT('',(-61.2653795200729,0.,14.));
#743=VERTEX_POINT('',#742);
#744=EDGE_CURVE('E383',#743,#734,#741,.T.);
#745=ORIENTED_EDGE('',*,*,#744,.F.);
#746=DIRECTION('',(1.,0.,0.));
#747=VECTOR('',#746,1.);
#748=CARTESIAN_POINT('',(-71.2653795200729,0.,14.));
#749=LINE('',#748,#747);
#750=EDGE_CURVE('E388',#726,#743,#749,.T.);
#751=ORIENTED_EDGE('',*,*,#750,.F.);
#752=EDGE_LOOP('',(#728,#736,#745,#751));
#753=FACE_BOUND('',#752,.T.);
#754=CARTESIAN_POINT('',(-71.2653795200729,0.,-15.5));
#755=DIRECTION('',(0.,-1.,0.));
#756=DIRECTION('',(0.,0.,1.));
#757=AXIS2_PLACEMENT_3D('',#754,#755,#756);
#758=CIRCLE('',#757,1.5);
#759=CARTESIAN_POINT('',(-71.2653795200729,0.,-14.));
#760=VERTEX_POINT('',#759);
#761=CARTESIAN_POINT('',(-71.2653795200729,0.,-17.));
#762=VERTEX_POINT('',#761);
#763=EDGE_CURVE('E329',#760,#762,#758,.T.);
#764=ORIENTED_EDGE('',*,*,#763,.F.);
#765=DIRECTION('',(-1.,0.,0.));
#766=VECTOR('',#765,1.);
#767=CARTESIAN_POINT('',(-71.2653795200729,0.,-14.));
#768=LINE('',#767,#766);
#769=CARTESIAN_POINT('',(-61.2653795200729,0.,-14.));
#770=VERTEX_POINT('',#769);
#771=EDGE_CURVE('E316',#770,#760,#768,.T.);
#772=ORIENTED_EDGE('',*,*,#771,.F.);
#773=CARTESIAN_POINT('',(-61.2653795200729,0.,-15.5));
#774=DIRECTION('',(0.,-1.,0.));
#775=DIRECTION('',(0.,0.,1.));
#776=AXIS2_PLACEMENT_3D('',#773,#774,#775);
#777=CIRCLE('',#776,1.5);
#778=CARTESIAN_POINT('',(-61.2653795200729,0.,-17.));
#779=VERTEX_POINT('',#778);
#780=EDGE_CURVE('E317',#779,#770,#777,.T.);
#781=ORIENTED_EDGE('',*,*,#780,.F.);
#782=DIRECTION('',(1.,0.,0.));
#783=VECTOR('',#782,1.);
#784=CARTESIAN_POINT('',(-71.2653795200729,0.,-17.));
#785=LINE('',#784,#783);
#786=EDGE_CURVE('E324',#762,#779,#785,.T.);
#787=ORIENTED_EDGE('',*,*,#786,.F.);
#788=EDGE_LOOP('',(#764,#772,#781,#787));
#789=FACE_BOUND('',#788,.T.);
#790=CARTESIAN_POINT('',(-102.265379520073,0.,15.5));
#791=DIRECTION('',(0.,-1.,0.));
#792=DIRECTION('',(0.,0.,-1.));
#793=AXIS2_PLACEMENT_3D('',#790,#791,#792);
#794=CIRCLE('',#793,1.50000000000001);
#795=CARTESIAN_POINT('',(-102.265379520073,0.,17.));
#796=VERTEX_POINT('',#795);
#797=CARTESIAN_POINT('',(-102.265379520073,0.,14.));
#798=VERTEX_POINT('',#797);
#799=EDGE_CURVE('E361',#796,#798,#794,.T.);
#800=ORIENTED_EDGE('',*,*,#799,.F.);
#801=DIRECTION('',(-1.,0.,0.));
#802=VECTOR('',#801,1.);
#803=CARTESIAN_POINT('',(-102.265379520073,0.,17.));
#804=LINE('',#803,#802);
#805=CARTESIAN_POINT('',(-92.2653795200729,0.,17.));
#806=VERTEX_POINT('',#805);
#807=EDGE_CURVE('E407',#806,#796,#804,.T.);
#808=ORIENTED_EDGE('',*,*,#807,.F.);
#809=CARTESIAN_POINT('',(-92.2653795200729,0.,15.5));
#810=DIRECTION('',(0.,-1.,0.));
#811=DIRECTION('',(0.,0.,-1.));
#812=AXIS2_PLACEMENT_3D('',#809,#810,#811);
#813=CIRCLE('',#812,1.49999999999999);
#814=CARTESIAN_POINT('',(-92.2653795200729,0.,14.));
#815=VERTEX_POINT('',#814);
#816=EDGE_CURVE('E421',#815,#806,#813,.T.);
#817=ORIENTED_EDGE('',*,*,#816,.F.);
#818=DIRECTION('',(1.,0.,0.));
#819=VECTOR('',#818,1.);
#820=CARTESIAN_POINT('',(-102.265379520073,0.,14.));
#821=LINE('',#820,#819);
#822=EDGE_CURVE('E418',#798,#815,#821,.T.);
#823=ORIENTED_EDGE('',*,*,#822,.F.);
#824=EDGE_LOOP('',(#800,#808,#817,#823));
#825=FACE_BOUND('',#824,.T.);
#826=CARTESIAN_POINT('',(122.625631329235,0.,-12.3743686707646));
#827=DIRECTION('',(0.,-1.,0.));
#828=DIRECTION('',(0.,0.,-1.));
#829=AXIS2_PLACEMENT_3D('',#826,#827,#828);
#830=CIRCLE('',#829,1.29999999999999);
#831=CARTESIAN_POINT('',(122.625631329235,0.,-13.6743686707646));
#832=VERTEX_POINT('',#831);
#833=EDGE_CURVE('E449',#832,#832,#830,.T.);
#834=ORIENTED_EDGE('',*,*,#833,.F.);
#835=EDGE_LOOP('',(#834));
#836=FACE_BOUND('',#835,.T.);
#837=CARTESIAN_POINT('',(147.374368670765,0.,-12.3743686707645));
#838=DIRECTION('',(0.,-1.,0.));
#839=DIRECTION('',(0.,0.,-1.));
#840=AXIS2_PLACEMENT_3D('',#837,#838,#839);
#841=CIRCLE('',#840,1.30000000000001);
#842=CARTESIAN_POINT('',(147.374368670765,0.,-13.6743686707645));
#843=VERTEX_POINT('',#842);
#844=EDGE_CURVE('E445',#843,#843,#841,.T.);
#845=ORIENTED_EDGE('',*,*,#844,.F.);
#846=EDGE_LOOP('',(#845));
#847=FACE_BOUND('',#846,.T.);
#848=CARTESIAN_POINT('',(147.374368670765,0.,12.3743686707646));
#849=DIRECTION('',(0.,-1.,0.));
#850=DIRECTION('',(0.,0.,-1.));
#851=AXIS2_PLACEMENT_3D('',#848,#849,#850);
#852=CIRCLE('',#851,1.30000000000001);
#853=CARTESIAN_POINT('',(147.374368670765,0.,11.0743686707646));
#854=VERTEX_POINT('',#853);
#855=EDGE_CURVE('E433',#854,#854,#852,.T.);
#856=ORIENTED_EDGE('',*,*,#855,.F.);
#857=EDGE_LOOP('',(#856));
#858=FACE_BOUND('',#857,.T.);
#859=CARTESIAN_POINT('',(122.625631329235,0.,12.3743686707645));
#860=DIRECTION('',(0.,-1.,0.));
#861=DIRECTION('',(0.,0.,-1.));
#862=AXIS2_PLACEMENT_3D('',#859,#860,#861);
#863=CIRCLE('',#862,1.29999999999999);
#864=CARTESIAN_POINT('',(122.625631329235,0.,11.0743686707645));
#865=VERTEX_POINT('',#864);
#866=EDGE_CURVE('E440',#865,#865,#863,.T.);
#867=ORIENTED_EDGE('',*,*,#866,.F.);
#868=EDGE_LOOP('',(#867));
#869=FACE_BOUND('',#868,.T.);
#870=CARTESIAN_POINT('',(135.,0.,0.));
#871=DIRECTION('',(0.,-1.,0.));
#872=DIRECTION('',(0.,0.,-1.));
#873=AXIS2_PLACEMENT_3D('',#870,#871,#872);
#874=CIRCLE('',#873,14.25);
#875=CARTESIAN_POINT('',(135.,0.,-14.25));
#876=VERTEX_POINT('',#875);
#877=EDGE_CURVE('E457',#876,#876,#874,.T.);
#878=ORIENTED_EDGE('',*,*,#877,.F.);
#879=EDGE_LOOP('',(#878));
#880=FACE_BOUND('',#879,.T.);
#881=CARTESIAN_POINT('',(-140.,0.,1.13697246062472E-10));
#882=DIRECTION('',(0.,-1.,0.));
#883=DIRECTION('',(0.,0.,-1.));
#884=AXIS2_PLACEMENT_3D('',#881,#882,#883);
#885=CIRCLE('',#884,9.99999999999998);
#886=CARTESIAN_POINT('',(-140.,0.,-9.99999999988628));
#887=VERTEX_POINT('',#886);
#888=EDGE_CURVE('E461',#887,#887,#885,.T.);
#889=ORIENTED_EDGE('',*,*,#888,.F.);
#890=EDGE_LOOP('',(#889));
#891=FACE_BOUND('',#890,.T.);
#892=ORIENTED_EDGE('',*,*,#128,.F.);
#893=CARTESIAN_POINT('',(-145.,0.,-9.99999999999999));
#894=DIRECTION('',(0.,-1.,0.));
#895=DIRECTION('',(0.,0.,-1.));
#896=AXIS2_PLACEMENT_3D('',#893,#894,#895);
#897=CIRCLE('',#896,20.);
#898=EDGE_CURVE('E504',#119,#71,#897,.T.);
#899=ORIENTED_EDGE('',*,*,#898,.T.);
#900=ORIENTED_EDGE('',*,*,#72,.F.);
#901=CARTESIAN_POINT('',(145.,0.,-10.));
#902=DIRECTION('',(0.,-1.,0.));
#903=DIRECTION('',(0.,0.,-1.));
#904=AXIS2_PLACEMENT_3D('',#901,#902,#903);
#905=CIRCLE('',#904,20.);
#906=EDGE_CURVE('E501',#69,#31,#905,.T.);
#907=ORIENTED_EDGE('',*,*,#906,.T.);
#908=ORIENTED_EDGE('',*,*,#32,.F.);
#909=CARTESIAN_POINT('',(145.,0.,10.));
#910=DIRECTION('',(0.,-1.,0.));
#911=DIRECTION('',(0.,0.,-1.));
#912=AXIS2_PLACEMENT_3D('',#909,#910,#911);
#913=CIRCLE('',#912,20.);
#914=EDGE_CURVE('E497',#29,#167,#913,.T.);
#915=ORIENTED_EDGE('',*,*,#914,.T.);
#916=ORIENTED_EDGE('',*,*,#168,.F.);
#917=CARTESIAN_POINT('',(-145.,0.,10.));
#918=DIRECTION('',(0.,-1.,0.));
#919=DIRECTION('',(0.,0.,-1.));
#920=AXIS2_PLACEMENT_3D('',#917,#918,#919);
#921=CIRCLE('',#920,20.);
#922=EDGE_CURVE('E502',#159,#127,#921,.T.);
#923=ORIENTED_EDGE('',*,*,#922,.T.);
#924=EDGE_LOOP('',(#892,#899,#900,#907,#908,#915,#916,#923));
#925=FACE_BOUND('',#924,.T.);
#926=ADVANCED_FACE('F254',(#568,#579,#590,#626,#637,#648,#659,#670,#681,#717,#753,#789,#825,
#836,#847,#858,#869,#880,#891,#925),#557,.T.);
#927=CARTESIAN_POINT('',(-145.,10.,-9.99999999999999));
#928=DIRECTION('',(0.,-1.,0.));
#929=DIRECTION('',(0.,0.,-1.));
#930=AXIS2_PLACEMENT_3D('',#927,#928,#929);
#931=CYLINDRICAL_SURFACE('',#930,20.);
#932=ORIENTED_EDGE('',*,*,#524,.F.);
#933=ORIENTED_EDGE('',*,*,#80,.F.);
#934=ORIENTED_EDGE('',*,*,#898,.F.);
#935=ORIENTED_EDGE('',*,*,#120,.F.);
#936=EDGE_LOOP('',(#932,#933,#934,#935));
#937=FACE_BOUND('',#936,.T.);
#938=ADVANCED_FACE('F550',(#937),#931,.T.);
#939=CARTESIAN_POINT('',(-145.,10.,10.));
#940=DIRECTION('',(0.,-1.,0.));
#941=DIRECTION('',(0.,0.,-1.));
#942=AXIS2_PLACEMENT_3D('',#939,#940,#941);
#943=CYLINDRICAL_SURFACE('',#942,20.);
#944=ORIENTED_EDGE('',*,*,#532,.F.);
#945=ORIENTED_EDGE('',*,*,#134,.F.);
#946=ORIENTED_EDGE('',*,*,#922,.F.);
#947=ORIENTED_EDGE('',*,*,#160,.F.);
#948=EDGE_LOOP('',(#944,#945,#946,#947));
#949=FACE_BOUND('',#948,.T.);
#950=ADVANCED_FACE('F557',(#949),#943,.T.);
#951=CARTESIAN_POINT('',(145.,10.,-10.));
#952=DIRECTION('',(0.,-1.,0.));
#953=DIRECTION('',(0.,0.,-1.));
#954=AXIS2_PLACEMENT_3D('',#951,#952,#953);
#955=CYLINDRICAL_SURFACE('',#954,20.);
#956=ORIENTED_EDGE('',*,*,#548,.F.);
#957=ORIENTED_EDGE('',*,*,#40,.F.);
#958=ORIENTED_EDGE('',*,*,#906,.F.);
#959=ORIENTED_EDGE('',*,*,#94,.F.);
#960=EDGE_LOOP('',(#956,#957,#958,#959));
#961=FACE_BOUND('',#960,.T.);
#962=ADVANCED_FACE('F538',(#961),#955,.T.);
#963=CARTESIAN_POINT('',(145.,10.,10.));
#964=DIRECTION('',(0.,-1.,0.));
#965=DIRECTION('',(0.,0.,-1.));
#966=AXIS2_PLACEMENT_3D('',#963,#964,#965);
#967=CYLINDRICAL_SURFACE('',#966,20.);
#968=ORIENTED_EDGE('',*,*,#540,.F.);
#969=ORIENTED_EDGE('',*,*,#174,.F.);
#970=ORIENTED_EDGE('',*,*,#914,.F.);
#971=ORIENTED_EDGE('',*,*,#54,.F.);
#972=EDGE_LOOP('',(#968,#969,#970,#971));
#973=FACE_BOUND('',#972,.T.);
#974=ADVANCED_FACE('F53',(#973),#967,.T.);
#975=CARTESIAN_POINT('',(-140.,10.,1.13697246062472E-10));
#976=DIRECTION('',(0.,-1.,0.));
#977=DIRECTION('',(0.,0.,-1.));
#978=AXIS2_PLACEMENT_3D('',#975,#976,#977);
#979=CYLINDRICAL_SURFACE('',#978,9.99999999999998);
#980=ORIENTED_EDGE('',*,*,#514,.F.);
#981=EDGE_LOOP('',(#980));
#982=FACE_BOUND('',#981,.T.);
#983=ORIENTED_EDGE('',*,*,#888,.T.);
#984=EDGE_LOOP('',(#983));
#985=FACE_BOUND('',#984,.T.);
#986=ADVANCED_FACE('F561',(#982,#985),#979,.F.);
#987=CARTESIAN_POINT('',(135.,10.,0.));
#988=DIRECTION('',(0.,-1.,0.));
#989=DIRECTION('',(0.,0.,-1.));
#990=AXIS2_PLACEMENT_3D('',#987,#988,#989);
#991=CYLINDRICAL_SURFACE('',#990,14.25);
#992=ORIENTED_EDGE('',*,*,#503,.F.);
#993=EDGE_LOOP('',(#992));
#994=FACE_BOUND('',#993,.T.);
#995=ORIENTED_EDGE('',*,*,#877,.T.);
#996=EDGE_LOOP('',(#995));
#997=FACE_BOUND('',#996,.T.);
#998=ADVANCED_FACE('F568',(#994,#997),#991,.F.);
#999=CARTESIAN_POINT('',(122.625631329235,10.,12.3743686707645));
#1000=DIRECTION('',(0.,-1.,0.));
#1001=DIRECTION('',(0.,0.,-1.));
#1002=AXIS2_PLACEMENT_3D('',#999,#1000,#1001);
#1003=CYLINDRICAL_SURFACE('',#1002,1.29999999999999);
#1004=ORIENTED_EDGE('',*,*,#492,.F.);
#1005=EDGE_LOOP('',(#1004));
#1006=FACE_BOUND('',#1005,.T.);
#1007=ORIENTED_EDGE('',*,*,#866,.T.);
#1008=EDGE_LOOP('',(#1007));
#1009=FACE_BOUND('',#1008,.T.);
#1010=ADVANCED_FACE('F611',(#1006,#1009),#1003,.F.);
#1011=CARTESIAN_POINT('',(147.374368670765,10.,12.3743686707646));
#1012=DIRECTION('',(0.,-1.,0.));
#1013=DIRECTION('',(0.,0.,-1.));
#1014=AXIS2_PLACEMENT_3D('',#1011,#1012,#1013);
#1015=CYLINDRICAL_SURFACE('',#1014,1.30000000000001);
#1016=ORIENTED_EDGE('',*,*,#481,.F.);
#1017=EDGE_LOOP('',(#1016));
#1018=FACE_BOUND('',#1017,.T.);
#1019=ORIENTED_EDGE('',*,*,#855,.T.);
#1020=EDGE_LOOP('',(#1019));
#1021=FACE_BOUND('',#1020,.T.);
#1022=ADVANCED_FACE('F624',(#1018,#1021),#1015,.F.);
#1023=CARTESIAN_POINT('',(147.374368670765,10.,-12.3743686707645));
#1024=DIRECTION('',(0.,-1.,0.));
#1025=DIRECTION('',(0.,0.,-1.));
#1026=AXIS2_PLACEMENT_3D('',#1023,#1024,#1025);
#1027=CYLINDRICAL_SURFACE('',#1026,1.30000000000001);
#1028=ORIENTED_EDGE('',*,*,#470,.F.);
#1029=EDGE_LOOP('',(#1028));
#1030=FACE_BOUND('',#1029,.T.);
#1031=ORIENTED_EDGE('',*,*,#844,.T.);
#1032=EDGE_LOOP('',(#1031));
#1033=FACE_BOUND('',#1032,.T.);
#1034=ADVANCED_FACE('F635',(#1030,#1033),#1027,.F.);
#1035=CARTESIAN_POINT('',(122.625631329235,10.,-12.3743686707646));
#1036=DIRECTION('',(0.,-1.,0.));
#1037=DIRECTION('',(0.,0.,-1.));
#1038=AXIS2_PLACEMENT_3D('',#1035,#1036,#1037);
#1039=CYLINDRICAL_SURFACE('',#1038,1.29999999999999);
#1040=ORIENTED_EDGE('',*,*,#459,.F.);
#1041=EDGE_LOOP('',(#1040));
#1042=FACE_BOUND('',#1041,.T.);
#1043=ORIENTED_EDGE('',*,*,#833,.T.);
#1044=EDGE_LOOP('',(#1043));
#1045=FACE_BOUND('',#1044,.T.);
#1046=ADVANCED_FACE('F644',(#1042,#1045),#1039,.F.);
#1047=CARTESIAN_POINT('',(-102.265379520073,10.,15.5));
#1048=DIRECTION('',(0.,-1.,0.));
#1049=DIRECTION('',(0.,0.,-1.));
#1050=AXIS2_PLACEMENT_3D('',#1047,#1048,#1049);
#1051=CYLINDRICAL_SURFACE('',#1050,1.50000000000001);
#1052=ORIENTED_EDGE('',*,*,#799,.T.);
#1053=DIRECTION('',(0.,-1.,0.));
#1054=VECTOR('',#1053,1.);
#1055=CARTESIAN_POINT('',(-102.265379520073,10.,14.));
#1056=LINE('',#1055,#1054);
#1057=EDGE_CURVE('E416',#432,#798,#1056,.T.);
#1058=ORIENTED_EDGE('',*,*,#1057,.F.);
#1059=ORIENTED_EDGE('',*,*,#433,.F.);
#1060=DIRECTION('',(0.,-1.,0.));
#1061=VECTOR('',#1060,1.);
#1062=CARTESIAN_POINT('',(-102.265379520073,10.,17.));
#1063=LINE('',#1062,#1061);
#1064=EDGE_CURVE('E426',#423,#796,#1063,.T.);
#1065=ORIENTED_EDGE('',*,*,#1064,.T.);
#1066=EDGE_LOOP('',(#1052,#1058,#1059,#1065));
#1067=FACE_BOUND('',#1066,.T.);
#1068=ADVANCED_FACE('F657',(#1067),#1051,.F.);
#1069=CARTESIAN_POINT('',(-102.265379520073,10.,17.));
#1070=DIRECTION('',(0.,0.,1.));
#1071=DIRECTION('',(1.,0.,0.));
#1072=AXIS2_PLACEMENT_3D('',#1069,#1070,#1071);
#1073=PLANE('',#1072);
#1074=ORIENTED_EDGE('',*,*,#807,.T.);
#1075=ORIENTED_EDGE('',*,*,#1064,.F.);
#1076=ORIENTED_EDGE('',*,*,#424,.F.);
#1077=DIRECTION('',(0.,-1.,0.));
#1078=VECTOR('',#1077,1.);
#1079=CARTESIAN_POINT('',(-92.2653795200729,10.,17.));
#1080=LINE('',#1079,#1078);
#1081=EDGE_CURVE('E428',#421,#806,#1080,.T.);
#1082=ORIENTED_EDGE('',*,*,#1081,.T.);
#1083=EDGE_LOOP('',(#1074,#1075,#1076,#1082));
#1084=FACE_BOUND('',#1083,.T.);
#1085=ADVANCED_FACE('F666',(#1084),#1073,.F.);
#1086=CARTESIAN_POINT('',(-92.2653795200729,10.,15.5));
#1087=DIRECTION('',(0.,-1.,0.));
#1088=DIRECTION('',(0.,0.,-1.));
#1089=AXIS2_PLACEMENT_3D('',#1086,#1087,#1088);
#1090=CYLINDRICAL_SURFACE('',#1089,1.49999999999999);
#1091=ORIENTED_EDGE('',*,*,#816,.T.);
#1092=ORIENTED_EDGE('',*,*,#1081,.F.);
#1093=ORIENTED_EDGE('',*,*,#448,.F.);
#1094=DIRECTION('',(0.,-1.,0.));
#1095=VECTOR('',#1094,1.);
#1096=CARTESIAN_POINT('',(-92.2653795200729,10.,14.));
#1097=LINE('',#1096,#1095);
#1098=EDGE_CURVE('E432',#440,#815,#1097,.T.);
#1099=ORIENTED_EDGE('',*,*,#1098,.T.);
#1100=EDGE_LOOP('',(#1091,#1092,#1093,#1099));
#1101=FACE_BOUND('',#1100,.T.);
#1102=ADVANCED_FACE('F679',(#1101),#1090,.F.);
#1103=CARTESIAN_POINT('',(-102.265379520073,10.,14.));
#1104=DIRECTION('',(0.,0.,-1.));
#1105=DIRECTION('',(-1.,0.,0.));
#1106=AXIS2_PLACEMENT_3D('',#1103,#1104,#1105);
#1107=PLANE('',#1106);
#1108=ORIENTED_EDGE('',*,*,#822,.T.);
#1109=ORIENTED_EDGE('',*,*,#1098,.F.);
#1110=ORIENTED_EDGE('',*,*,#441,.F.);
#1111=ORIENTED_EDGE('',*,*,#1057,.T.);
#1112=EDGE_LOOP('',(#1108,#1109,#1110,#1111));
#1113=FACE_BOUND('',#1112,.T.);
#1114=ADVANCED_FACE('F689',(#1113),#1107,.F.);
#1115=CARTESIAN_POINT('',(-71.2653795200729,10.,-15.5));
#1116=DIRECTION('',(0.,-1.,0.));
#1117=DIRECTION('',(0.,0.,-1.));
#1118=AXIS2_PLACEMENT_3D('',#1115,#1116,#1117);
#1119=CYLINDRICAL_SURFACE('',#1118,1.5);
#1120=ORIENTED_EDGE('',*,*,#763,.T.);
#1121=DIRECTION('',(0.,-1.,0.));
#1122=VECTOR('',#1121,1.);
#1123=CARTESIAN_POINT('',(-71.2653795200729,10.,-17.));
#1124=LINE('',#1123,#1122);
#1125=EDGE_CURVE('E310',#396,#762,#1124,.T.);
#1126=ORIENTED_EDGE('',*,*,#1125,.F.);
#1127=ORIENTED_EDGE('',*,*,#397,.F.);
#1128=DIRECTION('',(0.,-1.,0.));
#1129=VECTOR('',#1128,1.);
#1130=CARTESIAN_POINT('',(-71.2653795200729,10.,-14.));
#1131=LINE('',#1130,#1129);
#1132=EDGE_CURVE('E303',#387,#760,#1131,.T.);
#1133=ORIENTED_EDGE('',*,*,#1132,.T.);
#1134=EDGE_LOOP('',(#1120,#1126,#1127,#1133));
#1135=FACE_BOUND('',#1134,.T.);
#1136=ADVANCED_FACE('F696',(#1135),#1119,.F.);
#1137=CARTESIAN_POINT('',(-71.2653795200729,10.,-14.));
#1138=DIRECTION('',(0.,0.,1.));
#1139=DIRECTION('',(1.,0.,0.));
#1140=AXIS2_PLACEMENT_3D('',#1137,#1138,#1139);
#1141=PLANE('',#1140);
#1142=ORIENTED_EDGE('',*,*,#771,.T.);
#1143=ORIENTED_EDGE('',*,*,#1132,.F.);
#1144=ORIENTED_EDGE('',*,*,#388,.F.);
#1145=DIRECTION('',(0.,-1.,0.));
#1146=VECTOR('',#1145,1.);
#1147=CARTESIAN_POINT('',(-61.2653795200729,10.,-14.));
#1148=LINE('',#1147,#1146);
#1149=EDGE_CURVE('E315',#385,#770,#1148,.T.);
#1150=ORIENTED_EDGE('',*,*,#1149,.T.);
#1151=EDGE_LOOP('',(#1142,#1143,#1144,#1150));
#1152=FACE_BOUND('',#1151,.T.);
#1153=ADVANCED_FACE('F708',(#1152),#1141,.F.);
#1154=CARTESIAN_POINT('',(-61.2653795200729,10.,-15.5));
#1155=DIRECTION('',(0.,-1.,0.));
#1156=DIRECTION('',(0.,0.,-1.));
#1157=AXIS2_PLACEMENT_3D('',#1154,#1155,#1156);
#1158=CYLINDRICAL_SURFACE('',#1157,1.5);
#1159=ORIENTED_EDGE('',*,*,#780,.T.);
#1160=ORIENTED_EDGE('',*,*,#1149,.F.);
#1161=ORIENTED_EDGE('',*,*,#412,.F.);
#1162=DIRECTION('',(0.,-1.,0.));
#1163=VECTOR('',#1162,1.);
#1164=CARTESIAN_POINT('',(-61.2653795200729,10.,-17.));
#1165=LINE('',#1164,#1163);
#1166=EDGE_CURVE('E314',#404,#779,#1165,.T.);
#1167=ORIENTED_EDGE('',*,*,#1166,.T.);
#1168=EDGE_LOOP('',(#1159,#1160,#1161,#1167));
#1169=FACE_BOUND('',#1168,.T.);
#1170=ADVANCED_FACE('F716',(#1169),#1158,.F.);
#1171=CARTESIAN_POINT('',(-71.2653795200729,10.,-17.));
#1172=DIRECTION('',(0.,0.,-1.));
#1173=DIRECTION('',(-1.,0.,0.));
#1174=AXIS2_PLACEMENT_3D('',#1171,#1172,#1173);
#1175=PLANE('',#1174);
#1176=ORIENTED_EDGE('',*,*,#786,.T.);
#1177=ORIENTED_EDGE('',*,*,#1166,.F.);
#1178=ORIENTED_EDGE('',*,*,#405,.F.);
#1179=ORIENTED_EDGE('',*,*,#1125,.T.);
#1180=EDGE_LOOP('',(#1176,#1177,#1178,#1179));
#1181=FACE_BOUND('',#1180,.T.);
#1182=ADVANCED_FACE('F726',(#1181),#1175,.F.);
#1183=CARTESIAN_POINT('',(-71.2653795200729,10.,15.5));
#1184=DIRECTION('',(0.,-1.,0.));
#1185=DIRECTION('',(0.,0.,-1.));
#1186=AXIS2_PLACEMENT_3D('',#1183,#1184,#1185);
#1187=CYLINDRICAL_SURFACE('',#1186,1.5);
#1188=ORIENTED_EDGE('',*,*,#727,.T.);
#1189=DIRECTION('',(0.,-1.,0.));
#1190=VECTOR('',#1189,1.);
#1191=CARTESIAN_POINT('',(-71.2653795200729,10.,14.));
#1192=LINE('',#1191,#1190);
#1193=EDGE_CURVE('E374',#360,#726,#1192,.T.);
#1194=ORIENTED_EDGE('',*,*,#1193,.F.);
#1195=ORIENTED_EDGE('',*,*,#361,.F.);
#1196=DIRECTION('',(0.,-1.,0.));
#1197=VECTOR('',#1196,1.);
#1198=CARTESIAN_POINT('',(-71.2653795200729,10.,17.));
#1199=LINE('',#1198,#1197);
#1200=EDGE_CURVE('E330',#351,#724,#1199,.T.);
#1201=ORIENTED_EDGE('',*,*,#1200,.T.);
#1202=EDGE_LOOP('',(#1188,#1194,#1195,#1201));
#1203=FACE_BOUND('',#1202,.T.);
#1204=ADVANCED_FACE('F739',(#1203),#1187,.F.);
#1205=CARTESIAN_POINT('',(-71.2653795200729,10.,17.));
#1206=DIRECTION('',(0.,0.,1.));
#1207=DIRECTION('',(1.,0.,0.));
#1208=AXIS2_PLACEMENT_3D('',#1205,#1206,#1207);
#1209=PLANE('',#1208);
#1210=ORIENTED_EDGE('',*,*,#735,.T.);
#1211=ORIENTED_EDGE('',*,*,#1200,.F.);
#1212=ORIENTED_EDGE('',*,*,#352,.F.);
#1213=DIRECTION('',(0.,-1.,0.));
#1214=VECTOR('',#1213,1.);
#1215=CARTESIAN_POINT('',(-61.2653795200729,10.,17.));
#1216=LINE('',#1215,#1214);
#1217=EDGE_CURVE('E378',#349,#734,#1216,.T.);
#1218=ORIENTED_EDGE('',*,*,#1217,.T.);
#1219=EDGE_LOOP('',(#1210,#1211,#1212,#1218));
#1220=FACE_BOUND('',#1219,.T.);
#1221=ADVANCED_FACE('F746',(#1220),#1209,.F.);
#1222=CARTESIAN_POINT('',(-61.2653795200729,10.,15.5));
#1223=DIRECTION('',(0.,-1.,0.));
#1224=DIRECTION('',(0.,0.,-1.));
#1225=AXIS2_PLACEMENT_3D('',#1222,#1223,#1224);
#1226=CYLINDRICAL_SURFACE('',#1225,1.5);
#1227=ORIENTED_EDGE('',*,*,#744,.T.);
#1228=ORIENTED_EDGE('',*,*,#1217,.F.);
#1229=ORIENTED_EDGE('',*,*,#376,.F.);
#1230=DIRECTION('',(0.,-1.,0.));
#1231=VECTOR('',#1230,1.);
#1232=CARTESIAN_POINT('',(-61.2653795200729,10.,14.));
#1233=LINE('',#1232,#1231);
#1234=EDGE_CURVE('E376',#368,#743,#1233,.T.);
#1235=ORIENTED_EDGE('',*,*,#1234,.T.);
#1236=EDGE_LOOP('',(#1227,#1228,#1229,#1235));
#1237=FACE_BOUND('',#1236,.T.);
#1238=ADVANCED_FACE('F757',(#1237),#1226,.F.);
#1239=CARTESIAN_POINT('',(-71.2653795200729,10.,14.));
#1240=DIRECTION('',(0.,0.,-1.));
#1241=DIRECTION('',(-1.,0.,0.));
#1242=AXIS2_PLACEMENT_3D('',#1239,#1240,#1241);
#1243=PLANE('',#1242);
#1244=ORIENTED_EDGE('',*,*,#750,.T.);
#1245=ORIENTED_EDGE('',*,*,#1234,.F.);
#1246=ORIENTED_EDGE('',*,*,#369,.F.);
#1247=ORIENTED_EDGE('',*,*,#1193,.T.);
#1248=EDGE_LOOP('',(#1244,#1245,#1246,#1247));
#1249=FACE_BOUND('',#1248,.T.);
#1250=ADVANCED_FACE('F766',(#1249),#1243,.F.);
#1251=CARTESIAN_POINT('',(-102.265379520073,10.,-15.5));
#1252=DIRECTION('',(0.,-1.,0.));
#1253=DIRECTION('',(0.,0.,-1.));
#1254=AXIS2_PLACEMENT_3D('',#1251,#1252,#1253);
#1255=CYLINDRICAL_SURFACE('',#1254,1.50000000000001);
#1256=ORIENTED_EDGE('',*,*,#691,.T.);
#1257=DIRECTION('',(0.,-1.,0.));
#1258=VECTOR('',#1257,1.);
#1259=CARTESIAN_POINT('',(-102.265379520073,10.,-17.));
#1260=LINE('',#1259,#1258);
#1261=EDGE_CURVE('E339',#324,#690,#1260,.T.);
#1262=ORIENTED_EDGE('',*,*,#1261,.F.);
#1263=ORIENTED_EDGE('',*,*,#325,.F.);
#1264=DIRECTION('',(0.,-1.,0.));
#1265=VECTOR('',#1264,1.);
#1266=CARTESIAN_POINT('',(-102.265379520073,10.,-14.));
#1267=LINE('',#1266,#1265);
#1268=EDGE_CURVE('E350',#315,#688,#1267,.T.);
#1269=ORIENTED_EDGE('',*,*,#1268,.T.);
#1270=EDGE_LOOP('',(#1256,#1262,#1263,#1269));
#1271=FACE_BOUND('',#1270,.T.);
#1272=ADVANCED_FACE('F779',(#1271),#1255,.F.);
#1273=CARTESIAN_POINT('',(-102.265379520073,10.,-14.));
#1274=DIRECTION('',(0.,0.,1.));
#1275=DIRECTION('',(1.,0.,0.));
#1276=AXIS2_PLACEMENT_3D('',#1273,#1274,#1275);
#1277=PLANE('',#1276);
#1278=ORIENTED_EDGE('',*,*,#699,.T.);
#1279=ORIENTED_EDGE('',*,*,#1268,.F.);
#1280=ORIENTED_EDGE('',*,*,#316,.F.);
#1281=DIRECTION('',(0.,-1.,0.));
#1282=VECTOR('',#1281,1.);
#1283=CARTESIAN_POINT('',(-92.2653795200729,10.,-14.));
#1284=LINE('',#1283,#1282);
#1285=EDGE_CURVE('E344',#313,#698,#1284,.T.);
#1286=ORIENTED_EDGE('',*,*,#1285,.T.);
#1287=EDGE_LOOP('',(#1278,#1279,#1280,#1286));
#1288=FACE_BOUND('',#1287,.T.);
#1289=ADVANCED_FACE('F788',(#1288),#1277,.F.);
#1290=CARTESIAN_POINT('',(-92.2653795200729,10.,-15.5));
#1291=DIRECTION('',(0.,-1.,0.));
#1292=DIRECTION('',(0.,0.,-1.));
#1293=AXIS2_PLACEMENT_3D('',#1290,#1291,#1292);
#1294=CYLINDRICAL_SURFACE('',#1293,1.49999999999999);
#1295=ORIENTED_EDGE('',*,*,#708,.T.);
#1296=ORIENTED_EDGE('',*,*,#1285,.F.);
#1297=ORIENTED_EDGE('',*,*,#340,.F.);
#1298=DIRECTION('',(0.,-1.,0.));
#1299=VECTOR('',#1298,1.);
#1300=CARTESIAN_POINT('',(-92.2653795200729,10.,-17.));
#1301=LINE('',#1300,#1299);
#1302=EDGE_CURVE('E343',#332,#707,#1301,.T.);
#1303=ORIENTED_EDGE('',*,*,#1302,.T.);
#1304=EDGE_LOOP('',(#1295,#1296,#1297,#1303));
#1305=FACE_BOUND('',#1304,.T.);
#1306=ADVANCED_FACE('F796',(#1305),#1294,.F.);
#1307=CARTESIAN_POINT('',(-102.265379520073,10.,-17.));
#1308=DIRECTION('',(0.,0.,-1.));
#1309=DIRECTION('',(-1.,0.,0.));
#1310=AXIS2_PLACEMENT_3D('',#1307,#1308,#1309);
#1311=PLANE('',#1310);
#1312=ORIENTED_EDGE('',*,*,#714,.T.);
#1313=ORIENTED_EDGE('',*,*,#1302,.F.);
#1314=ORIENTED_EDGE('',*,*,#333,.F.);
#1315=ORIENTED_EDGE('',*,*,#1261,.T.);
#1316=EDGE_LOOP('',(#1312,#1313,#1314,#1315));
#1317=FACE_BOUND('',#1316,.T.);
#1318=ADVANCED_FACE('F807',(#1317),#1311,.F.);
#1319=CARTESIAN_POINT('',(-140.,0.,-17.5000000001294));
#1320=DIRECTION('',(0.,1.,0.));
#1321=DIRECTION('',(0.,0.,1.));
#1322=AXIS2_PLACEMENT_3D('',#1319,#1320,#1321);
#1323=CYLINDRICAL_SURFACE('',#1322,2.);
#1324=ORIENTED_EDGE('',*,*,#678,.F.);
#1325=EDGE_LOOP('',(#1324));
#1326=FACE_BOUND('',#1325,.T.);
#1327=ORIENTED_EDGE('',*,*,#304,.T.);
#1328=EDGE_LOOP('',(#1327));
#1329=FACE_BOUND('',#1328,.T.);
#1330=ADVANCED_FACE('F816',(#1326,#1329),#1323,.F.);
#1331=CARTESIAN_POINT('',(135.,10.,-17.5));
#1332=DIRECTION('',(0.,-1.,0.));
#1333=DIRECTION('',(0.,0.,-1.));
#1334=AXIS2_PLACEMENT_3D('',#1331,#1332,#1333);
#1335=CYLINDRICAL_SURFACE('',#1334,2.09999999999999);
#1336=ORIENTED_EDGE('',*,*,#667,.T.);
#1337=EDGE_LOOP('',(#1336));
#1338=FACE_BOUND('',#1337,.T.);
#1339=ORIENTED_EDGE('',*,*,#293,.F.);
#1340=EDGE_LOOP('',(#1339));
#1341=FACE_BOUND('',#1340,.T.);
#1342=ADVANCED_FACE('F829',(#1338,#1341),#1335,.F.);
#1343=CARTESIAN_POINT('',(117.5,10.,0.));
#1344=DIRECTION('',(0.,-1.,0.));
#1345=DIRECTION('',(0.,0.,-1.));
#1346=AXIS2_PLACEMENT_3D('',#1343,#1344,#1345);
#1347=CYLINDRICAL_SURFACE('',#1346,2.1);
#1348=ORIENTED_EDGE('',*,*,#282,.F.);
#1349=EDGE_LOOP('',(#1348));
#1350=FACE_BOUND('',#1349,.T.);
#1351=ORIENTED_EDGE('',*,*,#656,.T.);
#1352=EDGE_LOOP('',(#1351));
#1353=FACE_BOUND('',#1352,.T.);
#1354=ADVANCED_FACE('F836',(#1350,#1353),#1347,.F.);
#1355=CARTESIAN_POINT('',(152.5,10.,0.));
#1356=DIRECTION('',(0.,-1.,0.));
#1357=DIRECTION('',(0.,0.,-1.));
#1358=AXIS2_PLACEMENT_3D('',#1355,#1356,#1357);
#1359=CYLINDRICAL_SURFACE('',#1358,2.09999999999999);
#1360=ORIENTED_EDGE('',*,*,#271,.F.);
#1361=EDGE_LOOP('',(#1360));
#1362=FACE_BOUND('',#1361,.T.);
#1363=ORIENTED_EDGE('',*,*,#645,.T.);
#1364=EDGE_LOOP('',(#1363));
#1365=FACE_BOUND('',#1364,.T.);
#1366=ADVANCED_FACE('F854',(#1362,#1365),#1359,.F.);
#1367=CARTESIAN_POINT('',(135.,10.,17.5));
#1368=DIRECTION('',(0.,-1.,0.));
#1369=DIRECTION('',(0.,0.,-1.));
#1370=AXIS2_PLACEMENT_3D('',#1367,#1368,#1369);
#1371=CYLINDRICAL_SURFACE('',#1370,2.09999999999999);
#1372=ORIENTED_EDGE('',*,*,#260,.F.);
#1373=EDGE_LOOP('',(#1372));
#1374=FACE_BOUND('',#1373,.T.);
#1375=ORIENTED_EDGE('',*,*,#634,.T.);
#1376=EDGE_LOOP('',(#1375));
#1377=FACE_BOUND('',#1376,.T.);
#1378=ADVANCED_FACE('F865',(#1374,#1377),#1371,.F.);
#1379=CARTESIAN_POINT('',(-40.,0.,0.));
#1380=DIRECTION('',(0.,1.,0.));
#1381=DIRECTION('',(0.,0.,1.));
#1382=AXIS2_PLACEMENT_3D('',#1379,#1380,#1381);
#1383=CYLINDRICAL_SURFACE('',#1382,15.);
#1384=ORIENTED_EDGE('',*,*,#234,.T.);
#1385=DIRECTION('',(0.,1.,0.));
#1386=VECTOR('',#1385,1.);
#1387=CARTESIAN_POINT('',(-40.,0.,15.));
#1388=LINE('',#1387,#1386);
#1389=EDGE_CURVE('E234',#599,#222,#1388,.T.);
#1390=ORIENTED_EDGE('',*,*,#1389,.F.);
#1391=ORIENTED_EDGE('',*,*,#600,.F.);
#1392=DIRECTION('',(0.,1.,0.));
#1393=VECTOR('',#1392,1.);
#1394=CARTESIAN_POINT('',(-40.,0.,-15.));
#1395=LINE('',#1394,#1393);
#1396=EDGE_CURVE('E271',#597,#233,#1395,.T.);
#1397=ORIENTED_EDGE('',*,*,#1396,.T.);
#1398=EDGE_LOOP('',(#1384,#1390,#1391,#1397));
#1399=FACE_BOUND('',#1398,.T.);
#1400=ADVANCED_FACE('F239',(#1399),#1383,.F.);
#1401=CARTESIAN_POINT('',(-40.,0.,-15.));
#1402=DIRECTION('',(0.,0.,-1.));
#1403=DIRECTION('',(-1.,0.,0.));
#1404=AXIS2_PLACEMENT_3D('',#1401,#1402,#1403);
#1405=PLANE('',#1404);
#1406=ORIENTED_EDGE('',*,*,#242,.T.);
#1407=ORIENTED_EDGE('',*,*,#1396,.F.);
#1408=ORIENTED_EDGE('',*,*,#623,.F.);
#1409=DIRECTION('',(0.,1.,0.));
#1410=VECTOR('',#1409,1.);
#1411=CARTESIAN_POINT('',(90.,0.,-15.));
#1412=LINE('',#1411,#1410);
#1413=EDGE_CURVE('E272',#616,#241,#1412,.T.);
#1414=ORIENTED_EDGE('',*,*,#1413,.T.);
#1415=EDGE_LOOP('',(#1406,#1407,#1408,#1414));
#1416=FACE_BOUND('',#1415,.T.);
#1417=ADVANCED_FACE('F885',(#1416),#1405,.F.);
#1418=CARTESIAN_POINT('',(90.,0.,0.));
#1419=DIRECTION('',(0.,1.,0.));
#1420=DIRECTION('',(0.,0.,1.));
#1421=AXIS2_PLACEMENT_3D('',#1418,#1419,#1420);
#1422=CYLINDRICAL_SURFACE('',#1421,15.);
#1423=ORIENTED_EDGE('',*,*,#249,.T.);
#1424=ORIENTED_EDGE('',*,*,#1413,.F.);
#1425=ORIENTED_EDGE('',*,*,#617,.F.);
#1426=DIRECTION('',(0.,1.,0.));
#1427=VECTOR('',#1426,1.);
#1428=CARTESIAN_POINT('',(90.,0.,15.));
#1429=LINE('',#1428,#1427);
#1430=EDGE_CURVE('E243',#607,#224,#1429,.T.);
#1431=ORIENTED_EDGE('',*,*,#1430,.T.);
#1432=EDGE_LOOP('',(#1423,#1424,#1425,#1431));
#1433=FACE_BOUND('',#1432,.T.);
#1434=ADVANCED_FACE('F891',(#1433),#1422,.F.);
#1435=CARTESIAN_POINT('',(-40.,0.,15.));
#1436=DIRECTION('',(0.,0.,1.));
#1437=DIRECTION('',(1.,0.,0.));
#1438=AXIS2_PLACEMENT_3D('',#1435,#1436,#1437);
#1439=PLANE('',#1438);
#1440=ORIENTED_EDGE('',*,*,#225,.T.);
#1441=ORIENTED_EDGE('',*,*,#1430,.F.);
#1442=ORIENTED_EDGE('',*,*,#608,.F.);
#1443=ORIENTED_EDGE('',*,*,#1389,.T.);
#1444=EDGE_LOOP('',(#1440,#1441,#1442,#1443));
#1445=FACE_BOUND('',#1444,.T.);
#1446=ADVANCED_FACE('F249',(#1445),#1439,.F.);
#1447=CARTESIAN_POINT('',(-157.500000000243,0.,1.13492548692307E-10));
#1448=DIRECTION('',(0.,1.,0.));
#1449=DIRECTION('',(0.,0.,1.));
#1450=AXIS2_PLACEMENT_3D('',#1447,#1448,#1449);
#1451=CYLINDRICAL_SURFACE('',#1450,2.);
#1452=ORIENTED_EDGE('',*,*,#587,.F.);
#1453=EDGE_LOOP('',(#1452));
#1454=FACE_BOUND('',#1453,.T.);
#1455=ORIENTED_EDGE('',*,*,#213,.T.);
#1456=EDGE_LOOP('',(#1455));
#1457=FACE_BOUND('',#1456,.T.);
#1458=ADVANCED_FACE('F909',(#1454,#1457),#1451,.F.);
#1459=CARTESIAN_POINT('',(-140.,0.,17.5000000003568));
#1460=DIRECTION('',(0.,1.,0.));
#1461=DIRECTION('',(0.,0.,1.));
#1462=AXIS2_PLACEMENT_3D('',#1459,#1460,#1461);
#1463=CYLINDRICAL_SURFACE('',#1462,2.);
#1464=ORIENTED_EDGE('',*,*,#576,.F.);
#1465=EDGE_LOOP('',(#1464));
#1466=FACE_BOUND('',#1465,.T.);
#1467=ORIENTED_EDGE('',*,*,#202,.T.);
#1468=EDGE_LOOP('',(#1467));
#1469=FACE_BOUND('',#1468,.T.);
#1470=ADVANCED_FACE('F917',(#1466,#1469),#1463,.F.);
#1471=CARTESIAN_POINT('',(-122.499999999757,0.,1.13742348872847E-10));
#1472=DIRECTION('',(0.,1.,0.));
#1473=DIRECTION('',(0.,0.,1.));
#1474=AXIS2_PLACEMENT_3D('',#1471,#1472,#1473);
#1475=CYLINDRICAL_SURFACE('',#1474,2.);
#1476=ORIENTED_EDGE('',*,*,#565,.F.);
#1477=EDGE_LOOP('',(#1476));
#1478=FACE_BOUND('',#1477,.T.);
#1479=ORIENTED_EDGE('',*,*,#191,.T.);
#1480=EDGE_LOOP('',(#1479));
#1481=FACE_BOUND('',#1480,.T.);
#1482=ADVANCED_FACE('F927',(#1478,#1481),#1475,.F.);
#1483=CLOSED_SHELL('',(#58,#98,#138,#178,#552,#926,#938,#950,#962,#974,#986,#998,#1010,#1022,
#1034,#1046,#1068,#1085,#1102,#1114,#1136,#1153,#1170,#1182,#1204,#1221,#1238,#1250,#1272,#1289,
#1306,#1318,#1330,#1342,#1354,#1366,#1378,#1400,#1417,#1434,#1446,#1458,#1470,#1482));
#1484=MANIFOLD_SOLID_BREP('B2',#1483);
#1485=ADVANCED_BREP_SHAPE_REPRESENTATION('',(#18,#1484),#14);
#1486=SHAPE_DEFINITION_REPRESENTATION(#9,#1485);
ENDSEC;
END-ISO-10303-21;
